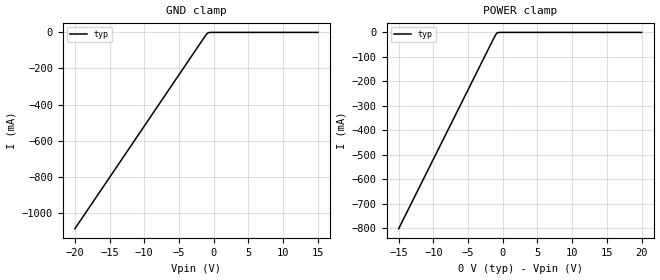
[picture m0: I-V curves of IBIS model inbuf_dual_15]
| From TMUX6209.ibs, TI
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| inbuf_dual_15
[Model]   inbuf_dual_15
Model_type   Input
|   typ   min   max
C_comp   6.362683e-13   NA   NA
[Voltage Range]   0   -15   15
[Temperature Range]   27   NA   NA
[Power Clamp Reference]   0   NA   NA
[GND Clamp Reference]   0   NA   NA
[GND Clamp]
|   Voltage   I(typ)   I(min)   I(max)
-20V      -1.088A    NA         NA
-1.263V   -21.77mA   NA         NA
-909.1mV  -4.356mA   NA         NA
-555.6mV  -13.14uA   NA         NA
15V       555.4nA    NA         NA
[POWER Clamp]
|   Voltage   I(typ)   I(min)   I(max)
-15V      -802.5mA   NA         NA
-1.212V   -19.1mA    NA         NA
-858.6mV  -2.503mA   NA         NA
-505.1mV  -7.686uA   NA         NA
20V       555.6nA    NA         NA
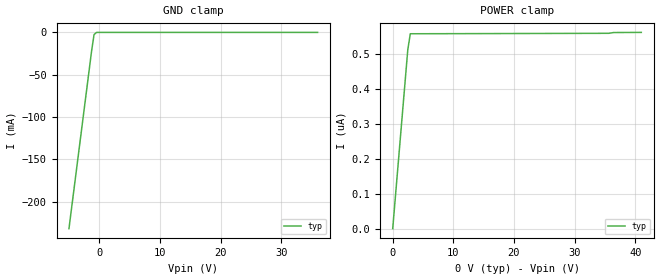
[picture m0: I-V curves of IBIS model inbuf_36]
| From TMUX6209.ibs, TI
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| inbuf_36
[Model]   inbuf_36
Model_type   Input
|   typ   min   max
C_comp   4.014581e-13   NA   NA
[Voltage Range]   36   0   36
[Temperature Range]   27   NA   NA
[Power Clamp Reference]   0   NA   NA
[GND Clamp Reference]   0   NA   NA
[GND Clamp]
|   Voltage   I(typ)   I(min)   I(max)
-5V       -231.7mA   NA         NA
-1.273V   -22.3mA    NA         NA
-858.6mV  -2.503mA   NA         NA
-444.4mV  -3.056uA   NA         NA
36V       560nA      NA         NA
[POWER Clamp]
|   Voltage   I(typ)   I(min)   I(max)
0V        -173.6pA   NA         NA
2.485V    511.5nA    NA         NA
2.899V    557.7nA    NA         NA
35.62V    559nA      NA         NA
36.44V    561.2nA    NA         NA
41V       561.6nA    NA         NA
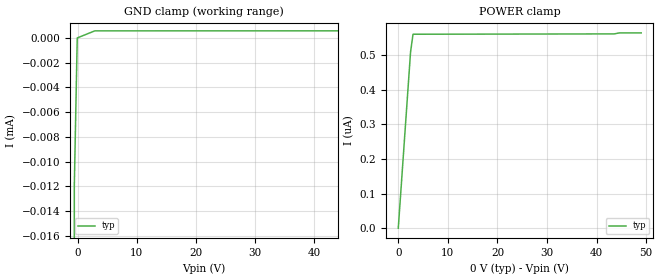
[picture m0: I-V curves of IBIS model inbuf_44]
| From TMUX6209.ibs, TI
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| inbuf_44
[Model]   inbuf_44
Model_type   Input
|   typ   min   max
C_comp   2.533030e-13   NA   NA
[Voltage Range]   44   0   44
[Temperature Range]   27   NA   NA
[Power Clamp Reference]   0   NA   NA
[GND Clamp Reference]   0   NA   NA
[GND Clamp]
|   Voltage   I(typ)   I(min)   I(max)
-5V       -231.7mA   NA         NA
-1.04V    -10.33mA   NA         NA
-545.5mV  -11.95uA   NA         NA
-50.51mV  -10.64nA   NA         NA
2.919V    560.7nA    NA         NA
44V       563.3nA    NA         NA
[POWER Clamp]
|   Voltage   I(typ)   I(min)   I(max)
0V        -210pA     NA         NA
2.475V    509.5nA    NA         NA
2.97V     561nA      NA         NA
43.56V    562nA      NA         NA
44.55V    564.8nA    NA         NA
49V       564.9nA    NA         NA
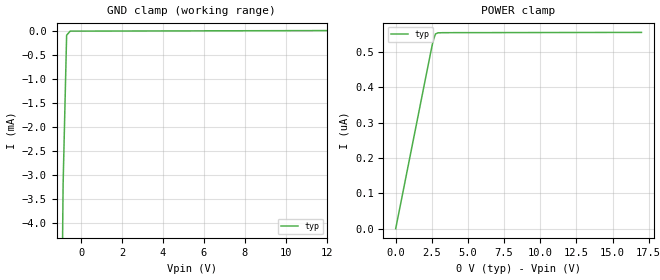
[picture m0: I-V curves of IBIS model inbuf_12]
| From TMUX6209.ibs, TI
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| inbuf_12
[Model]   inbuf_12
Model_type   Input
|   typ   min   max
C_comp   4.014581e-13   NA   NA
[Voltage Range]   12   0   12
[Temperature Range]   27   NA   NA
[Power Clamp Reference]   0   NA   NA
[GND Clamp Reference]   0   NA   NA
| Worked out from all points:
|   GND clamp passes 1 mA (typ) near -0.76 V on its own axis
[GND Clamp]
|   Voltage   I(typ)   I(min)   I(max)
-5V       -231.7mA   NA         NA
-1.051V   -10.83mA   NA         NA
-878.8mV  -3.196mA   NA         NA
-707.1mV  -96.01uA   NA         NA
-535.4mV  -10.79uA   NA         NA
12V       555.2nA    NA         NA
[POWER Clamp]
|   Voltage   I(typ)   I(min)   I(max)
0V        -67.62pA   NA         NA
2.404V    495.3nA    NA         NA
2.576V    529nA      NA         NA
2.747V    550.8nA    NA         NA
2.919V    554.1nA    NA         NA
3.263V    554.6nA    NA         NA
17V       555.4nA    NA         NA
